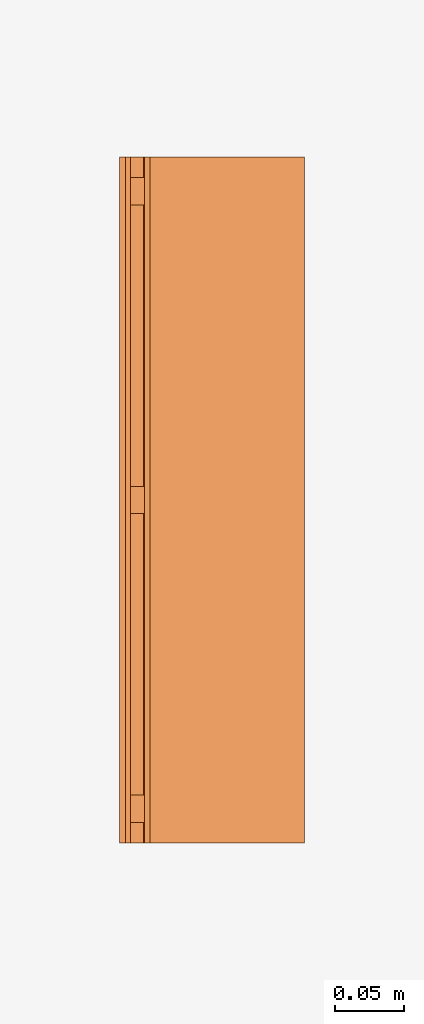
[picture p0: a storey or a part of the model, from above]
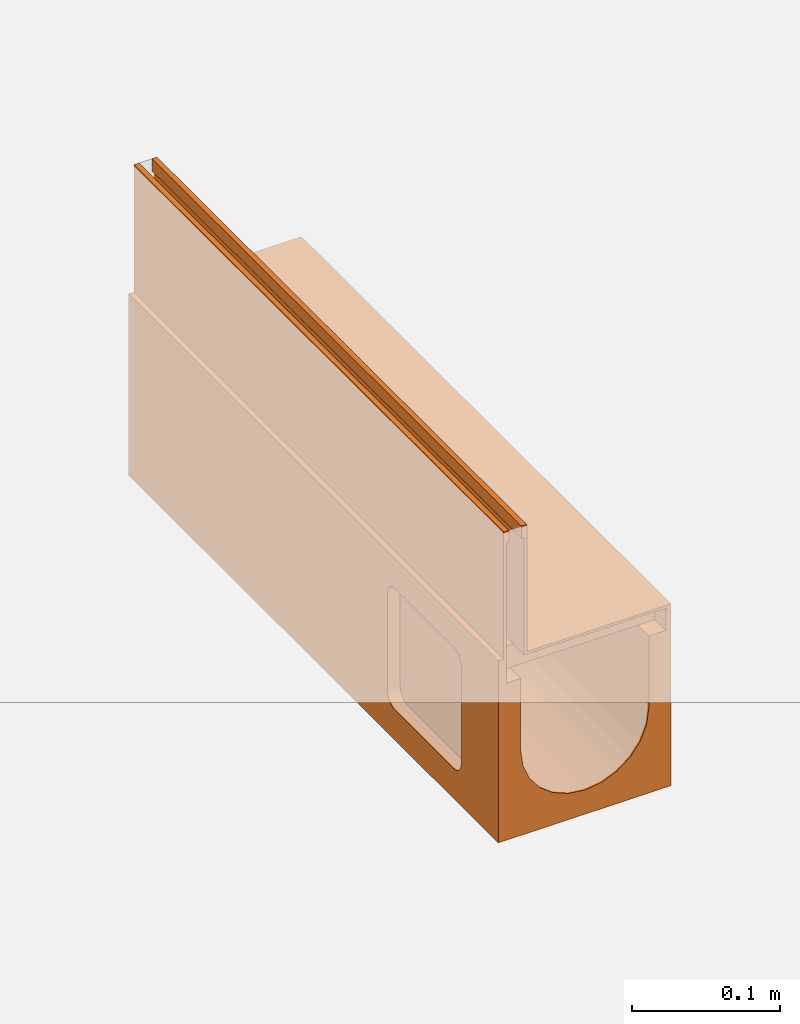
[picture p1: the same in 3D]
Properties of the parts of a building model (IFC2X3)

# File
Description: ViewDefinition [CoordinationView]
File name: 24050.ifc
Time: 2013-10-30T12:00:14
Written by: Autodesk Revit 2013
Made in: 20120221_2030(x64)

# IfcProject, Project Number
LongName: Project Name; Phase: Project Status

# IfcSite, Default
RefLatitude: 42, 21, 30, 344238; RefLongitude: -71, -3, -35, -194702; RefElevation: 0 mm

# IfcBuilding
Pset_BuildingCommon - NumberOfStoreys: 1
Other - Client Name: Owner; Project Issue Date: Issue Date; Project Status: Project Status; Project Number: Project Number; Project Name: Project Name; Project Address: ## Street City, State Zip

# IfcBuildingStorey, Level 1
LongName: Level 1; Elevation: 0 mm
Graphics - Symbol: M_Level Head - Circle: M_Level Head - Circle; Line Weight: 1; Symbol at End 1 Default: no; Line Pattern: Center; Symbol at End 2 Default: yes; Color: 0
Constraints - Elevation Base: 0; Elevation: 0 mm
Identity Data - Structural: no; Name: Level 1; Building Story: yes
Dimensions - Computation Height: 0 mm

# IfcBuildingElementProxy: 24050 - No 0.1J Constant Depth Channel - 500mm LG - Invert Depth 130mm, Civil-Drainage-Channel-ACO-MultiDrain-M100DS-Brickslot-Channel-System:24050 - No 0.1J Constant Depth Channel - 500mm LG - Invert Depth 130mm:24050 - No 0.1J Constant Depth Channel - 500mm LG - Invert Depth 130mm:196059
In: Level 1
Material: Stainless Steel (F), Vienite® Synthetic Resin Concrete
Phasing - Phase Created: New Construction
Dimensions - FloorCut_Length: -500 mm; Length: 1000 mm; Custom_Void_length: 0 mm; Brickslot Void Length: 500 mm; Brickslot Access Unit Void Depth: -6500 mm; Brickslot Void Depth: 0 mm; Volume: 4104233 mm3; EndCap Position: 500 mm; Brickslot Access Unit Void Bottom Depth: -6605 mm; EndCap_Height: 150 mm; Floor Cut Gap: 105 mm; InvDepth: 80 mm; Length Drain: -500 mm; FloorCut_Depth: 150 mm; ShallowOverallDepth: 75 mm; GratingLength: -1000 mm; Brickslot Access Unit Floor Cut Length: 500 mm; Depth: 150 mm; ShallowInvDepth: 55 mm; FloorCut_Width: 135 mm
Constraints - Moves With Nearby Elements: no; Level: Level: Level 1
Construction - 23475_Load Class C250 & D400_Brickslot Grating_Stainless Steel_1000mm Long: no; 23404_Universal Endcap (Male End): no; 23476_Load Class C250 & D400_Brickslot Grating_Stainless Steel_500mm Long: yes; 23477_Load Class C250 & D400_Brickslot_Access Unit_Stainless Steel_500mm Long: no; 23404_Universal Endcap (Female End): no; Constant Depth Channel: no; Shallow Depth Channel: no; Constant Depth Junction Channel: yes; 23410_Sump Unit: no; Shallow Depth Channel with seal: no
Pset_BuildingElementProxyCommon - Reference: 24050 - No 0.1J Constant Depth Channel - 500mm LG - Invert Depth 130mm
Data - Concrete Surround Volume - Load Class B 125 - C 250 - Concrete Pavement: 0.11m³/m; Pre-formed Outlet Ø: N/A; Concrete Surround Volume - Load Class A 15 - Concrete Pavement: 0.07m³/m; Product Weight: 8.6Kg; Installation - Concrete Grade: Refer to brochure; Product Standard: BS EN 1433:2002, CE marked; Channel C.S.A: 0.009m²; Invert Depth: 130mm; Product Dimensions: 500mm x 135mm x 150mm (LxWxH); Hydraulic Performance: http://www.aco.co.uk/download.php?id=173; Concrete Surround Volume - Load Class D 400 - Concrete Pavement: 0.17m³/m; Load Class: A 15 - D 400; ACO Hydraulic Design Software: http://www.acodesign.co.uk
General - TagNumber: 0; SerialNumber: 0
Identity Data - Installation guidelines: http://www.aco.co.uk/download.php?id=173; Model: ACO MultiDrain MDS Brickslot- M100DS; Address: ACO Business Park, Hitchin Road, Shefford, Bedfordshire, United Kingdom SG17 5TE; URL: www.aco.co.uk; e-mail Sales: customersupport@aco.co.uk; OmniClass Number: 23.70.50.24; Assembly Code: D2040; Product brochure: http://www.aco.co.uk/download.php?id=173; Assembly Description: Rain Water Drainage; Manufacturer: ACO Technologies plc - ACO Water Management Division; Watermark 2: This file is water marked and users are prohibited to reproduce, adapt, distribute this information; Price: POA - contact ACO; Cost: 0; Product Code: 24050; Maintenance guidelines: http://www.aco.co.uk/download.php?id=173; Type Comments: ACO MultiDrain M100DS 0.1J Constant Depth Junction Channel 500mm Long; Fax: +44 (0)1462 815895; Watermarked By: www.aco.co.uk; Telephone: +44 (0)1462 816666; e-mail Technical: technical@aco.co.uk; Watermark 1: This file is the property of ACO Technologies PLC; OmniClass Title: Rainwater Removal; Watermarked With: BIM Manager Premium Suite; Product Page URL: http://www.aco.co.uk/product_detail.php?id=58; Model Description: Channel drainage system
Materials and Finishes - Channel Colour: Brown; Channel Material: Vienite® Synthetic Resin Concrete; Edge Rail Material: Stainless Steel Grade 304; Edge Rail Colour: Self
Other - Created By: www.aco.co.uk; Revision: 1
Model Properties - Brickslot Access Unit Product code 23477: Load Class C250/D400 - Brickslot Access Unit Stainless Steel - 500mm long x 105mm high -10mm Slot- Intake area - 1000mm²/m - 6.4 Kg; End Cap Product code 23404: No 306 Universl End Cap - 135mm wide x 300mm long - Spigot Ø110mm x 50mm long - Silver - Polypropylene - 0.16kg; Brickslot Grating Product code 23475: N/A; Brickslot Grating Product code 23476: Load Class C250/D400 - Brickslot Stainless Steel - 500mm long x 105mm high -10mm Slot- Intake area - 1000mm²/m - 3.3 Kg
Green Building Properties - Channel Recycled Material Content: 20% minimum; Edge Rail Recyclable: Fully recyclable; Channel Recyclable: Fully recyclable; Edge Rail Recycled Material Content: Between 40% - 90%

# IfcOpeningElement: Recess (2)
In: Level 1
Dimensions - Perimeter: 20000 mm; Volume: 9988930000 mm3; Thickness: 400 mm; Area: 25000000 mm2
Constraints - Level: Level: Level 1; Room Bounding: yes; Related to Mass: no; Height Offset From Level: 0 mm
Phasing - Phase Created: New Construction
Structural - Enable Analytical Model: no; Structural: no
Analytical Properties - Absorptance: 0.1; Roughness: 1; Heat Transfer Coefficient (U): 2.0925; Thermal mass: 543920; Thermal Resistance (R): 0.477897
Construction - Function: 0; Default Thickness: 400 mm
Graphics - Coarse Scale Fill Color: 0
Materials and Finishes - Structural Material: Earth

# IfcSlab: Floor:Generic Floor - 400mm, Floor:Generic Floor - 400mm:193825
In: Level 1
PredefinedType: FLOOR; Material: Earth 400 mm
Dimensions - Perimeter: 20000 mm; Volume: 9988930000 mm3; Thickness: 400 mm; Area: 25000000 mm2
Constraints - Level: Level: Level 1; Room Bounding: yes; Related to Mass: no; Height Offset From Level: 0 mm
Phasing - Phase Created: New Construction
Structural - Enable Analytical Model: no; Structural: no
Pset_SlabCommon - Reference: Generic Floor - 400mm; IsExternal: no; LoadBearing: yes
Analytical Properties - Absorptance: 0.1; Roughness: 1; Heat Transfer Coefficient (U): 2.0925; Thermal mass: 543920; Thermal Resistance (R): 0.477897
Construction - Function: 0; Default Thickness: 400 mm
Graphics - Coarse Scale Fill Color: 0
Materials and Finishes - Structural Material: Earth
